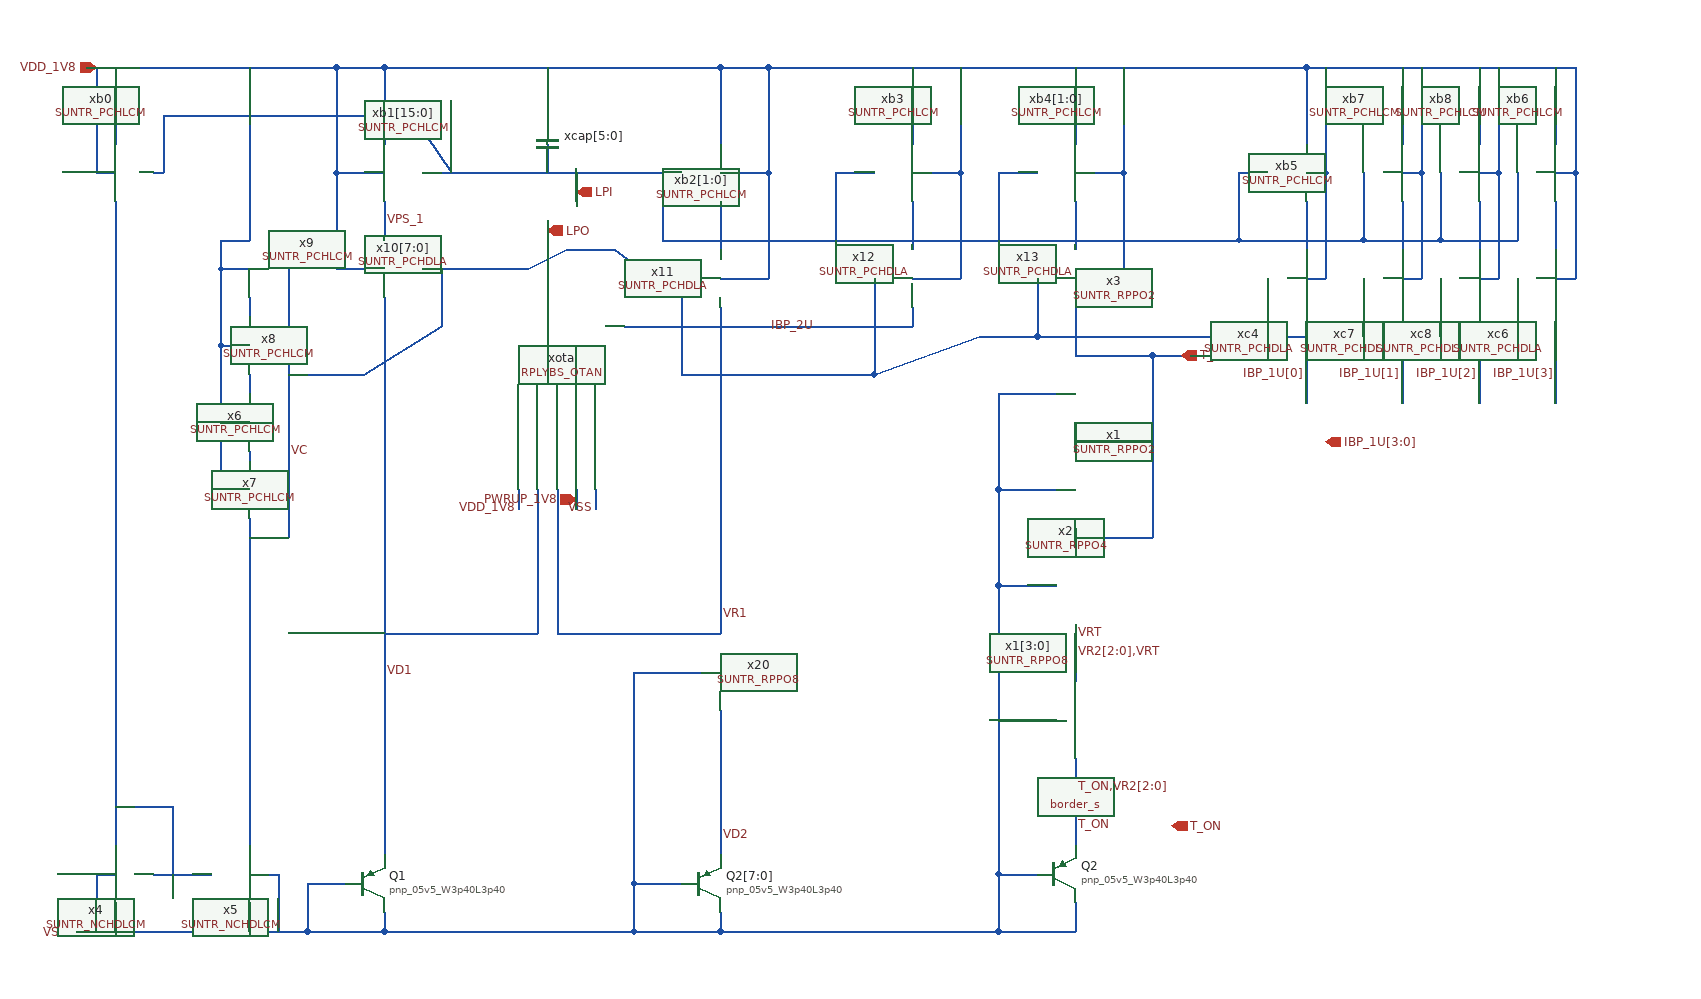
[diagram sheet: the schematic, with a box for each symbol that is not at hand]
v {xschem version=3.0.0 file_version=1.2 }
G {}
K {}
V {}
S {}
E {}
N -370 10 -330 10 {
lab=VSS}
N -370 10 -370 60 {
lab=VSS}
N -370 60 -290 60 {
lab=VSS}
N -290 40 -290 60 {
lab=VSS}
N -30 10 20 10 {
lab=VSS}
N -30 10 -30 60 {
lab=VSS}
N -30 60 60 60 {
lab=VSS}
N 60 40 60 60 {
lab=VSS}
N -290 60 -30 60 {
lab=VSS}
N -340 -730 -290 -730 {
lab=VDD_1V8}
N -340 -760 -340 -730 {
lab=VDD_1V8}
N -340 -840 -340 -760 {
lab=VDD_1V8}
N -340 -840 -290 -840 {
lab=VDD_1V8}
N -290 -840 -290 -760 {
lab=VDD_1V8}
N -290 -840 60 -840 {
lab=VDD_1V8}
N 60 -840 60 -760 {
lab=VDD_1V8}
N -250 -730 20 -730 {
lab=LPI}
N 60 -50 60 -20 {
lab=VD2}
N -30 -210 40 -210 {
lab=VSS}
N -30 -210 -30 10 {
lab=VSS}
N -600 -840 -340 -840 {
lab=VDD_1V8}
N -610 60 -370 60 {
lab=VSS}
N -120 -840 -120 -820 {
lab=VDD_1V8}
N -120 -750 -120 -730 {
lab=LPI}
N -130 -400 -130 -320 {
lab=VD1}
N -110 -370 -110 -250 {
lab=VR1}
N -150 -400 -150 -380 {
lab=VDD_1V8}
N -130 -320 -130 -250 {
lab=VD1}
N -90 -400 -90 -380 {
lab=PWRUP_1V8}
N -70 -400 -70 -380 {
lab=VSS}
N -110 -400 -110 -370 {
lab=VR1}
N -120 -680 -120 -660 {
lab=LPO}
N -90 -730 -90 -700 {
lab=LPI}
N 60 -730 110 -730 {
lab=VDD_1V8}
N 110 -840 110 -730 {
lab=VDD_1V8}
N 60 -840 110 -840 {
lab=VDD_1V8}
N 670 -840 670 -760 {
lab=VDD_1V8}
N 110 -840 670 -840 {
lab=VDD_1V8}
N 670 -840 710 -840 {
lab=VDD_1V8}
N 600 -730 630 -730 {
lab=LPI}
N 600 -730 600 -660 {
lab=LPI}
N 0 -660 600 -660 {
lab=LPI}
N 0 -730 0 -660 {
lab=LPI}
N 260 -730 310 -730 {
lab=VDD_1V8}
N 310 -840 310 -730 {
lab=VDD_1V8}
N 260 -840 260 -760 {
lab=VDD_1V8}
N 180 -730 220 -730 {
lab=LPI}
N 180 -730 180 -660 {
lab=LPI}
N -40 -570 260 -570 {
lab=IBP_2U}
N 430 -730 480 -730 {
lab=VDD_1V8}
N 480 -840 480 -730 {
lab=VDD_1V8}
N 430 -840 430 -760 {
lab=VDD_1V8}
N 350 -730 390 -730 {
lab=LPI}
N 350 -730 350 -660 {
lab=LPI}
N 350 0 390 0 {
lab=VSS}
N 350 0 350 60 {
lab=VSS}
N 350 60 430 60 {
lab=VSS}
N 430 30 430 60 {
lab=VSS}
N 60 60 350 60 {
lab=VSS}
N 350 -160 410 -160 {
lab=VSS}
N 350 -190 350 0 {
lab=VSS}
N 430 -120 430 -90 {
lab=T_ON,VR2[2:0]}
N 430 -60 430 -30 {
lab=T_ON}
N 430 -360 430 -340 {
lab=T_OP}
N 350 -300 410 -300 {
lab=VSS}
N 350 -400 410 -400 {
lab=VSS}
N 430 -460 430 -440 {
lab=T_OP}
N 350 -300 350 -190 {
lab=VSS}
N 350 -400 350 -300 {
lab=VSS}
N 350 -500 350 -400 {
lab=VSS}
N 350 -500 410 -500 {
lab=VSS}
N 60 -170 60 -50 {
lab=VD2}
N 510 -540 550 -540 {
lab=T_OP}
N 430 -230 430 -200 {
lab=VR2[2:0],VRT}
N 430 -260 430 -250 {
lab=VRT}
N 510 -540 510 -350 {
lab=T_OP}
N -120 -760 -120 -750 {
lab=LPI}
N 60 -310 60 -250 {
lab=VR1}
N -290 -310 -290 -20 {
lab=VD1}
N -110 -250 -50 -250 {
lab=VR1}
N -170 -250 -130 -250 {
lab=VD1}
N -290 -390 -290 -310 {
lab=VD1}
N 60 -390 60 -310 {
lab=VR1}
N -290 -250 -170 -250 {
lab=VD1}
N -50 -250 60 -250 {
lab=VR1}
N -570 -840 -570 -760 {
lab=VDD_1V8}
N -590 -730 -570 -730 {
lab=VDD_1V8}
N -590 -840 -590 -730 {
lab=VDD_1V8}
N -460 -630 -430 -630 {
lab=VDD_1V8}
N -460 -660 -460 -630 {
lab=VDD_1V8}
N -460 -660 -430 -660 {
lab=VDD_1V8}
N -430 -840 -430 -660 {
lab=VDD_1V8}
N -260 -790 -220 -730 {
lab=LPI}
N -520 -790 -260 -790 {
lab=LPI}
N -520 -790 -520 -730 {
lab=LPI}
N -530 -730 -520 -730 {
lab=LPI}
N -570 -700 -570 -30 {
lab=#net1}
N -590 -0 -570 -0 {
lab=VSS}
N -590 -0 -590 60 {
lab=VSS}
N -570 30 -570 60 {
lab=VSS}
N -430 30 -430 60 {
lab=VSS}
N -430 0 -400 0 {
lab=VSS}
N -400 0 -400 60 {
lab=VSS}
N -530 0 -470 0 {
lab=#net1}
N -430 -600 -430 -580 {
lab=#net2}
N -460 -550 -430 -550 {
lab=VDD_1V8}
N -430 -360 -430 -30 {
lab=VC}
N -430 -350 -390 -350 {
lab=VC}
N -390 -390 -390 -350 {
lab=VC}
N -390 -470 -390 -390 {
lab=VC}
N -390 -550 -390 -470 {
lab=VC}
N -390 -630 -390 -550 {
lab=VC}
N -290 -700 -290 -660 {
lab=VPS_1}
N -340 -630 -290 -630 {
lab=VDD_1V8}
N -340 -730 -340 -630 {
lab=VDD_1V8}
N -290 -600 -290 -390 {
lab=VD1}
N 60 -700 60 -650 {
lab=#net3}
N 60 -620 110 -620 {
lab=VDD_1V8}
N 110 -730 110 -620 {
lab=VDD_1V8}
N 60 -590 60 -390 {
lab=VR1}
N 260 -700 260 -650 {
lab=#net4}
N 260 -620 310 -620 {
lab=VDD_1V8}
N 310 -730 310 -620 {
lab=VDD_1V8}
N 430 -700 430 -650 {
lab=#net5}
N 430 -620 480 -620 {
lab=VDD_1V8}
N 480 -730 480 -620 {
lab=VDD_1V8}
N 430 -590 430 -540 {
lab=T_OP}
N 260 -590 260 -570 {
lab=IBP_2U}
N 20 -620 20 -520 {
lab=VC}
N 20 -520 220 -520 {
lab=VC}
N 220 -620 220 -520 {
lab=VC}
N 220 -520 330 -560 {
lab=VC}
N 330 -560 390 -560 {
lab=VC}
N 390 -620 390 -560 {
lab=VC}
N 390 -560 630 -560 {
lab=VC}
N 630 -620 630 -560 {
lab=VC}
N -120 -660 -120 -620 {
lab=LPO}
N -250 -630 -140 -630 {
lab=VC}
N -140 -630 -100 -650 {
lab=VC}
N -100 -650 -50 -650 {
lab=VC}
N -50 -650 -10 -620 {
lab=VC}
N -10 -620 20 -620 {
lab=VC}
N -230 -630 -230 -570 {
lab=VC}
N -310 -520 -230 -570 {
lab=VC}
N -390 -520 -310 -520 {
lab=VC}
N -570 -70 -510 -70 {
lab=#net1}
N -510 -70 -510 0 {
lab=#net1}
N -460 -630 -460 -550 {
lab=VDD_1V8}
N -430 -370 -430 -360 {
lab=VC}
N -460 -400 -430 -400 {
lab=VDD_1V8}
N -460 -550 -460 -400 {
lab=VDD_1V8}
N -430 -520 -430 -500 {
lab=#net6}
N -460 -470 -430 -470 {
lab=VDD_1V8}
N -430 -440 -430 -430 {
lab=#net7}
N 430 -350 510 -350 {
lab=T_OP}
N 430 -540 510 -540 {
lab=T_OP}
N 430 -450 510 -450 {
lab=T_OP}
N 670 -700 670 -650 {
lab=#net8}
N 670 -730 690 -730 {
lab=VDD_1V8}
N 690 -840 690 -730 {
lab=VDD_1V8}
N 690 -730 690 -620 {
lab=VDD_1V8}
N 670 -620 690 -620 {
lab=VDD_1V8}
N 770 -840 770 -760 {
lab=VDD_1V8}
N 770 -700 770 -650 {
lab=#net9}
N 770 -730 790 -730 {
lab=VDD_1V8}
N 790 -840 790 -730 {
lab=VDD_1V8}
N 790 -730 790 -620 {
lab=VDD_1V8}
N 770 -620 790 -620 {
lab=VDD_1V8}
N 850 -840 850 -760 {
lab=VDD_1V8}
N 850 -700 850 -650 {
lab=#net10}
N 850 -730 870 -730 {
lab=VDD_1V8}
N 870 -840 870 -730 {
lab=VDD_1V8}
N 870 -730 870 -620 {
lab=VDD_1V8}
N 850 -620 870 -620 {
lab=VDD_1V8}
N 930 -840 930 -760 {
lab=VDD_1V8}
N 930 -700 930 -650 {
lab=#net11}
N 930 -730 950 -730 {
lab=VDD_1V8}
N 950 -840 950 -730 {
lab=VDD_1V8}
N 950 -730 950 -620 {
lab=VDD_1V8}
N 930 -620 950 -620 {
lab=VDD_1V8}
N 710 -840 950 -840 {
lab=VDD_1V8}
N 730 -730 730 -670 {
lab=LPI}
N 730 -670 730 -660 {
lab=LPI}
N 600 -660 730 -660 {
lab=LPI}
N 730 -660 810 -660 {
lab=LPI}
N 810 -730 810 -660 {
lab=LPI}
N 810 -660 890 -660 {
lab=LPI}
N 890 -730 890 -660 {
lab=LPI}
N 670 -590 670 -490 {
lab=IBP_1U[0]}
N 770 -590 770 -490 {
lab=IBP_1U[1]}
N 850 -590 850 -490 {
lab=IBP_1U[2]}
N 930 -590 930 -490 {
lab=IBP_1U[3]}
N 630 -560 890 -560 {
lab=VC}
N 890 -620 890 -560 {
lab=VC}
N 810 -620 810 -560 {
lab=VC}
N 730 -620 730 -560 {
lab=VC}
C {cborder/border_s.sym} 520 0 0 0 {
user="Carsten Wulff"
company="Carsten Wulff Software"}
C {devices/ipin.sym} -590 -840 0 0 {name=p1 lab=VDD_1V8}
C {devices/ipin.sym} -600 60 0 0 {name=p2 lab=VSS}
C {devices/ipin.sym} -90 -390 3 0 {name=p3 lab=PWRUP_1V8}
C {devices/opin.sym} -90 -710 1 0 {name=p6 lab=LPI}
C {devices/opin.sym} -120 -670 3 0 {name=p7 lab=LPO}
C {devices/opin.sym} 690 -450 1 0 {name=p8 lab=IBP_1U[3:0]}
C {sky130_fd_pr/pnp_05v5.sym} -310 10 0 0 {name=Q1
model=pnp_05v5_W3p40L3p40
spiceprefix=X
}
C {sky130_fd_pr/pnp_05v5.sym} 40 10 0 0 {name=Q2[7:0]
model=pnp_05v5_W3p40L3p40
spiceprefix=X
}
C {SUN_TR_SKY130NM/SUNTR_RPPO8.sym} 60 -250 1 0 {name=x20 }
C {RPLY_BIAS_SKY130NM/RPLYBS_OTAN.sym} -110 -550 3 0 {name=xota}
C {devices/lab_pin.sym} -150 -380 3 0 {name=l1 sig_type=std_logic lab=VDD_1V8}
C {devices/lab_pin.sym} -70 -380 3 0 {name=l3 sig_type=std_logic lab=VSS}
C {devices/lab_pin.sym} -290 -210 0 1 {name=l2 sig_type=std_logic lab=VD1}
C {devices/lab_pin.sym} 60 -40 0 1 {name=l4 sig_type=std_logic lab=VD2}
C {devices/lab_pin.sym} 60 -270 0 1 {name=l5 sig_type=std_logic lab=VR1}
C {devices/lab_wire.sym} 160 -570 0 0 {name=l6 sig_type=std_logic lab=IBP_2U}
C {sky130_fd_pr/pnp_05v5.sym} 410 0 0 0 {name=Q2
model=pnp_05v5_W3p40L3p40
spiceprefix=X
}
C {SUN_TR_SKY130NM/SUNTR_RPPO8.sym} 430 -200 1 0 {name=x1[3:0] }
C {devices/lab_pin.sym} 430 -90 0 1 {name=l7 sig_type=std_logic lab=T_ON,VR2[2:0]}
C {devices/lab_pin.sym} 430 -230 0 1 {name=l8 sig_type=std_logic lab=VR2[2:0],VRT}
C {SUN_TR_SKY130NM/SUNTR_RPPO4.sym} 430 -340 1 0 {name=x2 }
C {SUN_TR_SKY130NM/SUNTR_RPPO2.sym} 430 -440 1 0 {name=x1 }
C {SUN_TR_SKY130NM/SUNTR_RPPO2.sym} 430 -540 1 0 {name=x3 }
C {devices/opin.sym} 540 -540 0 0 {name=p4 lab=T_OP}
C {devices/lab_pin.sym} 430 -50 0 1 {name=l9 sig_type=std_logic lab=T_ON}
C {devices/lab_pin.sym} 430 -250 0 1 {name=l10 sig_type=std_logic lab=VRT}
C {devices/opin.sym} 530 -50 0 0 {name=p5 lab=T_ON}
C {SUN_TR_SKY130NM/SUNTR_CAP_20.sym} -120 -760 0 0 {name=xcap[5:0] }
C {SUN_TR_SKY130NM/SUNTR_NCHDLCM.sym} -530 0 0 1 {name=x4 }
C {SUN_TR_SKY130NM/SUNTR_NCHDLCM.sym} -470 0 0 0 {name=x5 }
C {SUN_TR_SKY130NM/SUNTR_PCHLCM.sym} -390 -550 0 1 {name=x8 }
C {SUN_TR_SKY130NM/SUNTR_PCHLCM.sym} -390 -630 0 1 {name=x9 }
C {SUN_TR_SKY130NM/SUNTR_PCHDLA.sym} -250 -630 0 1 {name=x10[7:0] }
C {SUN_TR_SKY130NM/SUNTR_PCHDLA.sym} 20 -620 0 0 {name=x11 }
C {SUN_TR_SKY130NM/SUNTR_PCHDLA.sym} 220 -620 0 0 {name=x12 }
C {SUN_TR_SKY130NM/SUNTR_PCHDLA.sym} 390 -620 0 0 {name=x13 }
C {SUN_TR_SKY130NM/SUNTR_PCHDLA.sym} 630 -620 0 0 {name=xc4}
C {devices/lab_pin.sym} -390 -440 0 1 {name=l12 sig_type=std_logic lab=VC}
C {devices/lab_pin.sym} -290 -680 0 1 {name=l13 sig_type=std_logic lab=VPS_1}
C {SUN_TR_SKY130NM/SUNTR_PCHLCM.sym} -390 -470 0 1 {name=x6 }
C {SUN_TR_SKY130NM/SUNTR_PCHLCM.sym} -390 -400 0 1 {name=x7 }
C {SUN_TR_SKY130NM/SUNTR_PCHLCM.sym} -250 -730 0 1 {name=xb1[15:0] }
C {SUN_TR_SKY130NM/SUNTR_PCHLCM.sym} 20 -730 0 0 {name=xb2[1:0] }
C {SUN_TR_SKY130NM/SUNTR_PCHLCM.sym} 220 -730 0 0 {name=xb3 }
C {SUN_TR_SKY130NM/SUNTR_PCHLCM.sym} 390 -730 0 0 {name=xb4[1:0] }
C {SUN_TR_SKY130NM/SUNTR_PCHLCM.sym} 630 -730 0 0 {name=xb5 }
C {SUN_TR_SKY130NM/SUNTR_PCHDLA.sym} 730 -620 0 0 {name=xc7}
C {SUN_TR_SKY130NM/SUNTR_PCHLCM.sym} 730 -730 0 0 {name=xb7 }
C {SUN_TR_SKY130NM/SUNTR_PCHDLA.sym} 810 -620 0 0 {name=xc8}
C {SUN_TR_SKY130NM/SUNTR_PCHLCM.sym} 810 -730 0 0 {name=xb8 }
C {SUN_TR_SKY130NM/SUNTR_PCHDLA.sym} 890 -620 0 0 {name=xc6}
C {SUN_TR_SKY130NM/SUNTR_PCHLCM.sym} 890 -730 0 0 {name=xb6 }
C {devices/lab_wire.sym} 670 -520 1 1 {name=l11 sig_type=std_logic lab=IBP_1U[0]}
C {devices/lab_wire.sym} 770 -520 1 1 {name=l14 sig_type=std_logic lab=IBP_1U[1]}
C {devices/lab_wire.sym} 850 -520 1 1 {name=l15 sig_type=std_logic lab=IBP_1U[2]}
C {devices/lab_wire.sym} 930 -520 1 1 {name=l16 sig_type=std_logic lab=IBP_1U[3]}
C {SUN_TR_SKY130NM/SUNTR_PCHLCM.sym} -530 -730 0 1 {name=xb0 }
